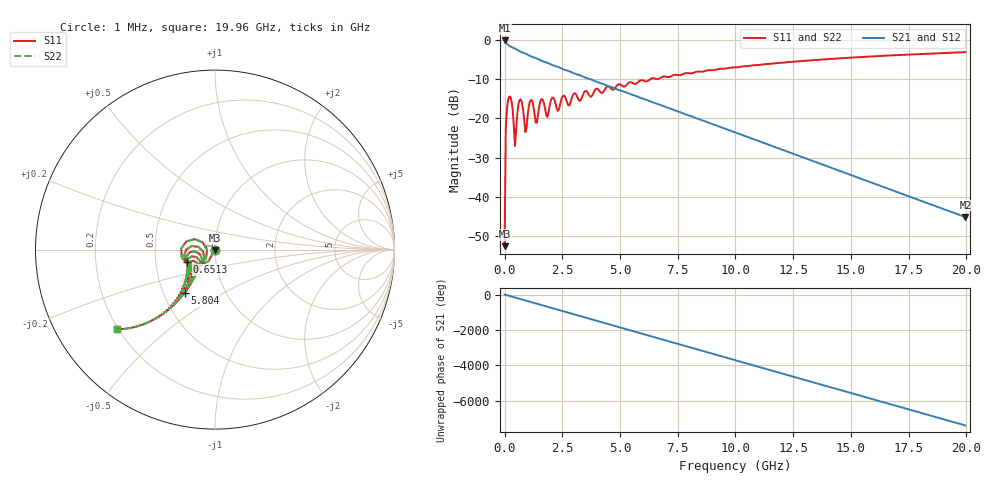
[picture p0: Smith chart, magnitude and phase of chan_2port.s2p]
! Created with skrf 2.1.0 (http://scikit-rf.org).
# Hz S MA R 50.0
!freq magS11 angS11 magS21 angS21 magS12 angS12 magS22 angS22
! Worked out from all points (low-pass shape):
!   400 points, 1 MHz to 19.96 GHz, reference 50 ohm
!   highest |S21| = -0.07 dB at 1 MHz (marker M1); lowest = -45.2 dB at 19.96 GHz (marker M2)
!   |S21| within 3 dB of the highest: start of sweep to 736.1 MHz
!   lowest |S11| = -52.7 dB at 1 MHz (marker M3), VSWR 1.00, Z = 49.8 - j0.152 ohm
!   |S11| at or under -10 dB: start of sweep to 6.304 GHz
!   |S22| runs from -52.7 to -3.1 dB; largest |S21 - S12| = 1.3e-14
!   S11 on the Smith chart (normalised r, x): 1 MHz: 1.00, -0.00; 651.3 MHz: 0.72, -0.10; 5.804 GHz: 0.64, -0.34; 19.96 GHz: 0.20, -0.34
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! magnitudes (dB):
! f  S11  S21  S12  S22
! 1 MHz  -52.7  -0.1  -0.1  -52.7
! 51.02 MHz  -22.7  -0.6  -0.6  -22.7
! 101 MHz  -17.6  -0.9  -0.9  -17.6
! 301.1 MHz  -15.6  -1.8  -1.8  -15.6
! 451.2 MHz  -27.1  -2.1  -2.1  -27.1
! 651.3 MHz  -15.3  -2.8  -2.8  -15.3
! 751.3 MHz  -15.9  -3.1  -3.1  -15.9
! 901.4 MHz  -23.5  -3.4  -3.4  -23.5
! 1.152 GHz  -15.2  -4.2  -4.2  -15.2
! 1.352 GHz  -21.1  -4.6  -4.6  -21.1
! 1.602 GHz  -15.1  -5.3  -5.3  -15.1
! 1.852 GHz  -19.6  -5.8  -5.8  -19.6
! 2.052 GHz  -14.8  -6.3  -6.3  -14.8
! 2.302 GHz  -18.1  -6.8  -6.8  -18.1
! 2.552 GHz  -14.1  -7.5  -7.5  -14.1
! 3.353 GHz  -14.6  -9.2  -9.2  -14.6
! 5.804 GHz  -10.6  -14.5  -14.5  -10.6
! 6.704 GHz  -9.8  -16.5  -16.5  -9.8
! 10.01 GHz  -7.0  -23.6  -23.6  -7.0
! 13.36 GHz  -5.1  -30.9  -30.9  -5.1
! 16.66 GHz  -3.9  -38.1  -38.1  -3.9
! 19.96 GHz  -3.1  -45.2  -45.2  -3.1
